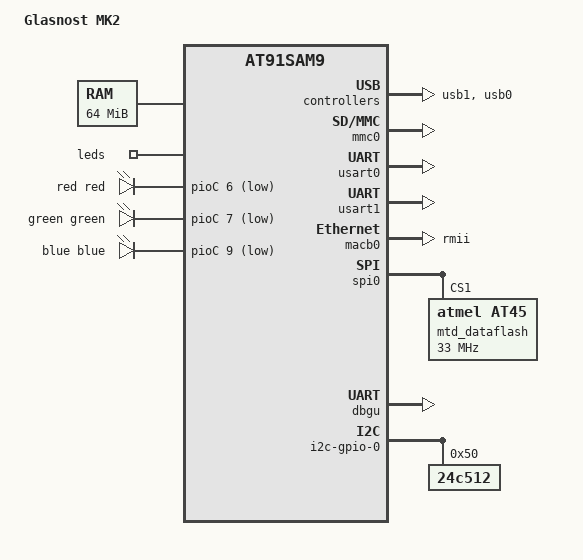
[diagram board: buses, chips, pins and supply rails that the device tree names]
/*
 * Device Tree file for Glasnost MK2 board
 * Based loosley on AT91SAM9260 EK
 *  Copyright (C) 2021 Vadim Radu <vadim@printarescu.ro>,
 */

/dts-v1/;
#include "at91sam9260.dtsi"

/ {
	model = "Glasnost MK2";
	compatible = "atmel,at91sam9260ek", "atmel,at91sam9260", "atmel,at91sam9";

	chosen {
		u-boot,dm-pre-reloc;
		stdout-path = &dbgu;
	};

	memory {
		reg = <0x20000000 0x4000000>;
	};

	clocks {
		slow_xtal {
			clock-frequency = <32768>;
		};

		main_xtal {
			clock-frequency = <18432000>;
		};
	};

	ahb {
		apb {
			usb1: gadget@fffa4000 {
				atmel,vbus-gpio = <&pioB 17 GPIO_ACTIVE_HIGH>; //PB17 is tied to a VUSB resistor divider 
				status = "okay";
			};

			mmc0: mmc@fffa8000 { // Slot 0 pins of MCI are used for mmc
				pinctrl-0 = <
					&pinctrl_board_mmc0_slot0
					&pinctrl_mmc0_clk
					&pinctrl_mmc0_slot0_cmd_dat0
					&pinctrl_mmc0_slot0_dat1_3>;
				status = "okay";
				slot@0 {
					reg = <0>;
					bus-width = <4>;
					cd-gpios = <&pioB 19 GPIO_ACTIVE_HIGH>; //PB19 is pulled up when card is inserted
				};
			};

			usart0: serial@fffb0000 {
				pinctrl-0 =
					<&pinctrl_usart0
					 &pinctrl_usart0_rts
					 &pinctrl_usart0_cts
					 &pinctrl_usart0_dtr_dsr
					 &pinctrl_usart0_dcd
					 &pinctrl_usart0_ri>;
				status = "okay";
			};

			usart1: serial@fffb4000 {
				status = "okay";
			};

			ssc0: ssc@fffbc000 {
				status = "okay";
				pinctrl-0 = <&pinctrl_ssc0_tx>;
			};

			macb0: ethernet@fffc4000 {
				phy-mode = "rmii";
				status = "okay";
			};

			spi0: spi@fffc8000 {
				cs-gpios = <&pioA 3 0>, <0>, <0>, <0>;
				mtd_dataflash@1 {
					compatible = "atmel,at45", "atmel,dataflash";
					spi-max-frequency = <33000000>;
					reg = <1>;
				};
			};

			dbgu: serial@fffff200 {
				u-boot,dm-pre-reloc;
				status = "okay";
			};

			pinctrl@fffff400 {
				board {
					pinctrl_board_mmc0_slot0: mmc0_slot0-board {
						atmel,pins =
							<AT91_PIOB 19 AT91_PERIPH_GPIO AT91_PINCTRL_PULL_UP_DEGLITCH>;
					};
				};
			};

			shdwc@fffffd10 {
				atmel,wakeup-counter = <10>;
				atmel,wakeup-rtt-timer;
			};

			rtc@fffffd20 {
				atmel,rtt-rtc-time-reg = <&gpbr 0x0>;
				status = "okay";
			};

			watchdog@fffffd40 {
				status = "okay";
			};

			gpbr: syscon@fffffd50 {
				status = "okay";
			};
		};

		usb0: ohci@00500000 {
			num-ports = <2>;
			status = "okay";
		};

	gpio_keys {
		compatible = "gpio-keys";

	i2c-gpio-0 {
		#address-cells = <1>;
		#size-cells = <0>;
		status = "okay";

		24c512@50 {
			compatible = "24c512";
			reg = <0x50>;
		};
	};

	leds {
		compatible = "gpio-leds";

		led0 {
			label = "red";
      color = LED_COLOR_ID_RED;
			gpios = <&pioC 6 GPIO_ACTIVE_LOW>;
      panic-indicator = true;
			
		};

		led1 {
			label = "green";
      color = LED_COLOR_ID_GREEN;
			gpios = <&pioC 7 GPIO_ACTIVE_LOW>;
      linux,default-trigger = "heartbeat";
		};
    
    led2 {
			label = "blue";
			color = LED_COLOR_ID_BLUE;
      gpios = <&pioC 9 GPIO_ACTIVE_LOW>;
		};
	};
};
